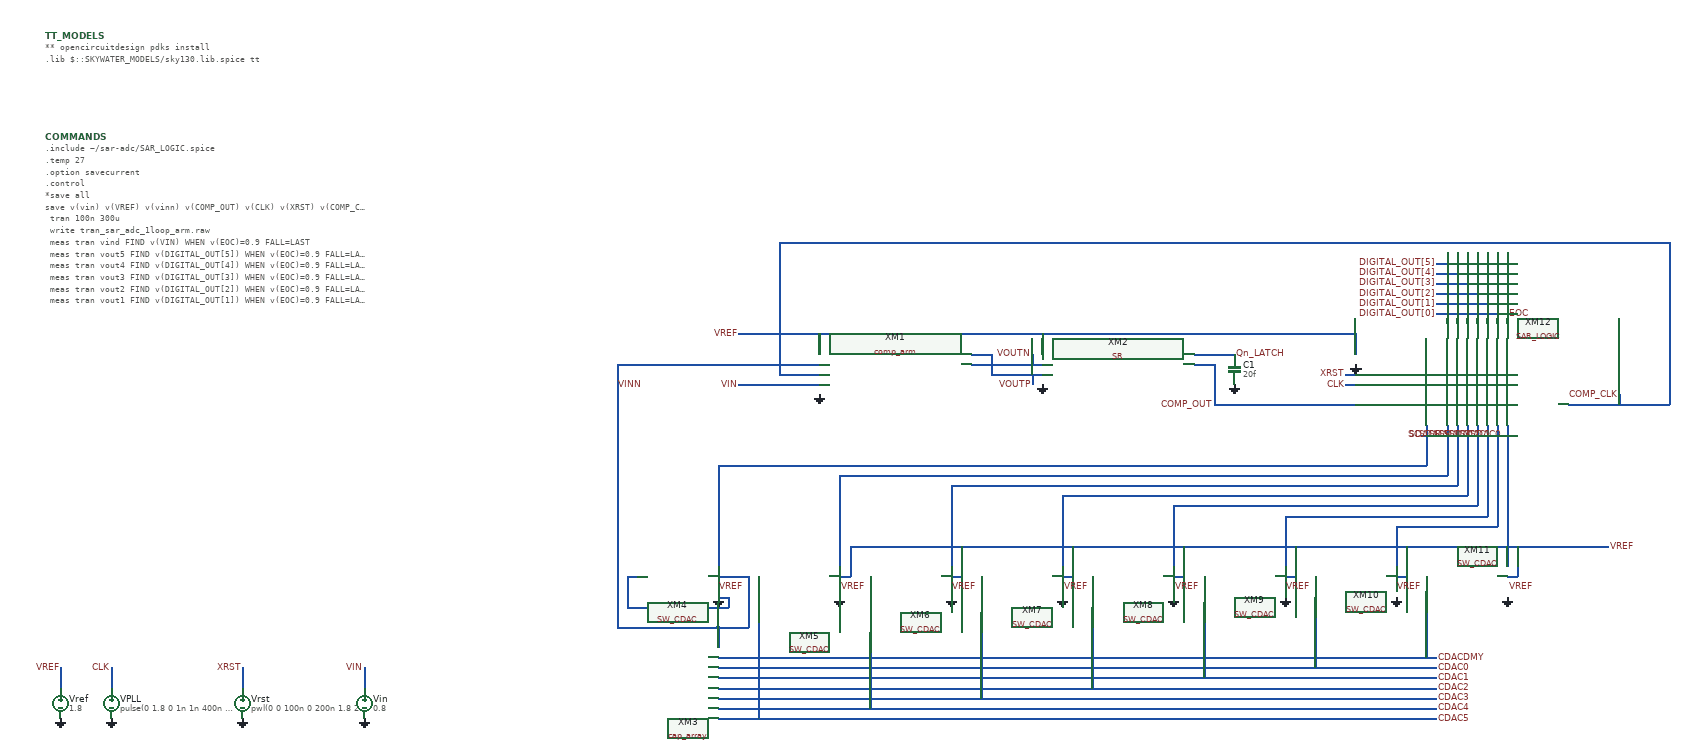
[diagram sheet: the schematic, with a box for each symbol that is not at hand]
v {xschem version=3.4.8RC file_version=1.3}
G {}
K {}
V {}
S {}
F {}
E {}
N 60 -300 60 -260 {
lab=VREF}
N 160 -300 160 -260 {
lab=CLK}
N 420 -300 420 -260 {
lab=XRST}
N 660 -300 660 -260 {
lab=VIN}
N 2340 -820 2620 -820 {
lab=COMP_OUT}
N 2600 -860 2620 -860 {
lab=CLK}
N 2600 -880 2620 -880 {
lab=XRST}
N 2920 -780 2920 -690 {
lab=SDAC0}
N 2910 -760 2920 -760 {
lab=SDAC0}
N 2900 -780 2900 -690 {
lab=SDAC1}
N 2890 -760 2900 -760 {
lab=SDAC1}
N 2880 -780 2880 -690 {
lab=SDAC2}
N 2870 -760 2880 -760 {
lab=SDAC2}
N 2860 -780 2860 -690 {
lab=SDAC3}
N 2850 -760 2860 -760 {
lab=SDAC3}
N 2840 -780 2840 -690 {
lab=SDAC4}
N 2830 -760 2840 -760 {
lab=SDAC4}
N 2820 -780 2820 -690 {
lab=SDAC5}
N 2810 -760 2820 -760 {
lab=SDAC5}
N 2800 -780 2800 -690 {
lab=SDAC6}
N 2790 -760 2800 -760 {
lab=SDAC6}
N 2760 -780 2760 -700 {
lab=SC}
N 2750 -760 2760 -760 {
lab=SC}
N 3040 -820 3240 -820 {
lab=COMP_CLK}
N 3140 -840 3140 -820 {
lab=COMP_CLK}
N 1860 -920 1900 -920 {
lab=VOUTP}
N 1860 -900 1880 -900 {
lab=VOUTN}
N 1360 -320 2780 -320 {
lab=CDACDMY}
N 1360 -300 2780 -300 {
lab=CDAC0}
N 1360 -280 2780 -280 {
lab=CDAC1}
N 1360 -260 2780 -260 {
lab=CDAC2}
N 1360 -240 2780 -240 {
lab=CDAC3}
N 1360 -220 2780 -220 {
lab=CDAC4}
N 1360 -200 2780 -200 {
lab=CDAC5}
N 1600 -680 2800 -680 {
lab=SDAC6}
N 1600 -680 1600 -500 {
lab=SDAC6}
N 1820 -660 1820 -500 {
lab=SDAC5}
N 1820 -660 2820 -660 {
lab=SDAC5}
N 2040 -640 2840 -640 {
lab=SDAC4}
N 2040 -640 2040 -500 {
lab=SDAC4}
N 2260 -620 2260 -500 {
lab=SDAC3}
N 2260 -620 2860 -620 {
lab=SDAC3}
N 2480 -600 2880 -600 {
lab=SDAC2}
N 2480 -600 2480 -500 {
lab=SDAC2}
N 2700 -580 2700 -500 {
lab=SDAC1}
N 2920 -690 2920 -500 {
lab=SDAC0}
N 1360 -700 2760 -700 {
lab=SC}
N 1360 -700 1360 -500 {
lab=SC}
N 1180 -480 1200 -480 {
lab=GND}
N 1180 -480 1180 -420 {
lab=GND}
N 1180 -420 1380 -420 {
lab=GND}
N 1380 -440 1380 -420 {
lab=GND}
N 1360 -440 1380 -440 {
lab=GND}
N 1360 -380 1360 -340 {
lab=VINN}
N 1160 -380 1360 -380 {
lab=VINN}
N 1160 -900 1160 -380 {
lab=VINN}
N 1160 -900 1560 -900 {
lab=VINN}
N 1360 -480 1420 -480 {
lab=VINN}
N 1420 -480 1420 -380 {
lab=VINN}
N 1360 -380 1420 -380 {
lab=VINN}
N 2700 -580 2900 -580 {
lab=SDAC1}
N 1480 -880 1560 -880 {
lab=COMP_CLK}
N 1480 -1140 1480 -880 {
lab=COMP_CLK}
N 1480 -1140 3240 -1140 {
lab=COMP_CLK}
N 3240 -1140 3240 -820 {
lab=COMP_CLK}
N 1620 -540 3120 -540 {
lab=VREF}
N 1600 -480 1620 -480 {
lab=VREF}
N 1620 -540 1620 -480 {
lab=VREF}
N 1820 -480 1840 -480 {
lab=VREF}
N 1840 -540 1840 -480 {
lab=VREF}
N 2040 -480 2060 -480 {
lab=VREF}
N 2060 -540 2060 -480 {
lab=VREF}
N 2260 -480 2280 -480 {
lab=VREF}
N 2280 -540 2280 -480 {
lab=VREF}
N 2480 -480 2500 -480 {
lab=VREF}
N 2500 -540 2500 -480 {
lab=VREF}
N 2700 -480 2720 -480 {
lab=VREF}
N 2720 -540 2720 -480 {
lab=VREF}
N 2920 -480 2940 -480 {
lab=VREF}
N 2940 -540 2940 -480 {
lab=VREF}
N 1400 -860 1560 -860 {
lab=VIN}
N 1980 -880 1980 -860 {
lab=VOUTP}
N 1980 -920 1980 -900 {
lab=VOUTN}
N 2800 -690 2800 -680 {
lab=SDAC6}
N 2820 -690 2820 -660 {
lab=SDAC5}
N 2840 -690 2840 -640 {
lab=SDAC4}
N 2860 -690 2860 -620 {
lab=SDAC3}
N 2880 -690 2880 -600 {
lab=SDAC2}
N 2900 -690 2900 -580 {
lab=SDAC1}
N 1880 -480 1880 -240 {
lab=CDAC3}
N 1660 -480 1660 -220 {
lab=CDAC4}
N 1440 -480 1440 -200 {
lab=CDAC5}
N 2800 -1120 2800 -980 {
lab=DIGITAL_OUT[5]}
N 2780 -1100 2800 -1100 {
lab=DIGITAL_OUT[5]}
N 2780 -1080 2820 -1080 {
lab=DIGITAL_OUT[4]}
N 2780 -1060 2840 -1060 {
lab=DIGITAL_OUT[3]}
N 2780 -1040 2860 -1040 {
lab=DIGITAL_OUT[2]}
N 2780 -1020 2880 -1020 {
lab=DIGITAL_OUT[1]}
N 2780 -1000 2900 -1000 {
lab=DIGITAL_OUT[0]}
N 2820 -1120 2820 -980 {
lab=DIGITAL_OUT[4]}
N 2840 -1120 2840 -980 {
lab=DIGITAL_OUT[3]}
N 2860 -1120 2860 -980 {
lab=DIGITAL_OUT[2]}
N 2880 -1120 2880 -980 {
lab=DIGITAL_OUT[1]}
N 2900 -1120 2900 -980 {
lab=DIGITAL_OUT[0]}
N 2920 -1120 2920 -980 {
lab=EOC}
N 2100 -480 2100 -260 {lab=CDAC2}
N 2320 -480 2320 -280 {lab=CDAC1}
N 2540 -480 2540 -300 {lab=CDAC0}
N 2760 -480 2760 -320 {lab=CDACDMY}
N 1400 -960 2620 -960 {lab=VREF}
N 2620 -960 2620 -920 {lab=VREF}
N 2000 -960 2000 -920 {lab=VREF}
N 1560 -960 1560 -920 {lab=VREF}
N 2360 -920 2380 -920 {lab=Qn_LATCH}
N 2300 -900 2340 -900 {lab=COMP_OUT}
N 2340 -900 2340 -820 {lab=COMP_OUT}
N 2300 -920 2360 -920 {lab=Qn_LATCH}
N 1880 -900 2000 -900 {lab=VOUTN}
N 1900 -920 1900 -880 {lab=VOUTP}
N 1900 -880 2000 -880 {lab=VOUTP}
C {devices/vsource.sym} 60 -230 0 0 {name=Vref value=1.8 savecurrent=false}
C {devices/gnd.sym} 160 -200 0 0 {name=l2 lab=GND}
C {devices/gnd.sym} 60 -200 0 0 {name=l3 lab=GND}
C {devices/lab_pin.sym} 160 -300 0 0 {name=p2 sig_type=std_logic lab=CLK}
C {devices/lab_pin.sym} 420 -300 0 0 {name=p9 sig_type=std_logic lab=XRST}
C {devices/gnd.sym} 420 -200 0 0 {name=l1 lab=GND}
C {devices/lab_pin.sym} 660 -300 2 1 {name=p25 sig_type=std_logic lab=VIN}
C {devices/gnd.sym} 660 -200 0 0 {name=l22 lab=GND}
C {devices/code.sym} 30 -1550 0 0 {name=TT_MODELS
only_toplevel=true
format="tcleval( @value )"
value="
** opencircuitdesign pdks install
.lib $::SKYWATER_MODELS/sky130.lib.spice tt
"
spice_ignore=false}
C {devices/vsource.sym} 160 -230 0 0 {name=VPLL value="pulse(0 1.8 0 1n 1n 400n 800n)" savecurrent=false}
C {devices/vsource.sym} 420 -230 0 0 {name=Vrst value="pwl(0 0 100n 0 200n 1.8 200n 1.8)" savecurrent=false}
C {devices/vsource.sym} 660 -230 0 0 {name=Vin value=0.8 savecurrent=false}
C {devices/lab_pin.sym} 60 -300 2 1 {name=p45 sig_type=std_logic lab=VREF}
C {devices/simulator_commands_shown.sym} 30 -1350 0 0 {name=COMMANDS
simulator=ngspice
only_toplevel=false 
value=".include ~/sar-adc/SAR_LOGIC.spice
.temp 27
.option savecurrent
.control
*save all
save v(vin) v(VREF) v(vinn) v(COMP_OUT) v(CLK) v(XRST) v(COMP_CLK) v(eoc) v(CDACDMY) v(CDAC0) v(CDAC1) v(CDAC2) v(CDAC3) v(CDAC4) v(CDAC5) v(digital_out[5]) v(digital_out[4]) v(digital_out[3]) v(digital_out[2]) v(digital_out[1]) v(digital_out[0]) v(SC) v(SDAC0) v(SDAC1) v(SDAC2) v(SDAC3) v(SDAC4) v(SDAC5) v(SDAC6)



	tran 100n 300u
	write tran_sar_adc_1loop_arm.raw
	meas tran vind FIND v(VIN) WHEN v(EOC)=0.9 FALL=LAST
	meas tran vout5 FIND v(DIGITAL_OUT[5]) WHEN v(EOC)=0.9 FALL=LAST
	meas tran vout4 FIND v(DIGITAL_OUT[4]) WHEN v(EOC)=0.9 FALL=LAST
	meas tran vout3 FIND v(DIGITAL_OUT[3]) WHEN v(EOC)=0.9 FALL=LAST
	meas tran vout2 FIND v(DIGITAL_OUT[2]) WHEN v(EOC)=0.9 FALL=LAST
	meas tran vout1 FIND v(DIGITAL_OUT[1]) WHEN v(EOC)=0.9 FALL=LAST
	meas tran vout0 FIND v(DIGITAL_OUT[0]) WHEN v(EOC)=0.9 FALL=LAST
	print vind >> tran_sar_adc_1loop_out_typ.txt
*	print vinn >> tran_sar_adc_1loop_out_typ.txt
	print vout5 >> tran_sar_adc_1loop_out_typ.txt
	print vout4 >> tran_sar_adc_1loop_out_typ.txt
	print vout3 >> tran_sar_adc_1loop_out_typ.txt
	print vout2 >> tran_sar_adc_1loop_out_typ.txt
	print vout1 >> tran_sar_adc_1loop_out_typ.txt
	print vout0 >> tran_sar_adc_1loop_out_typ.txt

.endc
"}
C {devices/lab_pin.sym} 2600 -860 0 0 {name=p5 sig_type=std_logic lab=CLK}
C {devices/lab_pin.sym} 2600 -880 0 0 {name=p7 sig_type=std_logic lab=XRST}
C {devices/lab_pin.sym} 2910 -760 3 0 {name=p10 sig_type=std_logic lab=SDAC0}
C {devices/lab_pin.sym} 2890 -760 3 0 {name=p11 sig_type=std_logic lab=SDAC1}
C {devices/lab_pin.sym} 2870 -760 3 0 {name=p12 sig_type=std_logic lab=SDAC2}
C {devices/lab_pin.sym} 2850 -760 3 0 {name=p13 sig_type=std_logic lab=SDAC3}
C {devices/lab_pin.sym} 2830 -760 3 0 {name=p14 sig_type=std_logic lab=SDAC4}
C {devices/lab_pin.sym} 2810 -760 3 0 {name=p15 sig_type=std_logic lab=SDAC5}
C {devices/lab_pin.sym} 2790 -760 3 0 {name=p16 sig_type=std_logic lab=SDAC6}
C {devices/lab_pin.sym} 2750 -760 3 0 {name=p19 sig_type=std_logic lab=SC}
C {devices/lab_pin.sym} 3140 -840 0 0 {name=p20 sig_type=std_logic lab=COMP_CLK}
C {devices/gnd.sym} 1360 -440 0 1 {name=l4 lab=GND}
C {devices/gnd.sym} 1600 -440 0 1 {name=l5 lab=GND}
C {devices/gnd.sym} 1820 -440 0 1 {name=l6 lab=GND}
C {devices/gnd.sym} 2040 -440 0 1 {name=l7 lab=GND}
C {devices/gnd.sym} 2260 -440 0 1 {name=l8 lab=GND}
C {devices/gnd.sym} 2480 -440 0 1 {name=l9 lab=GND}
C {devices/gnd.sym} 2700 -440 0 1 {name=l10 lab=GND}
C {devices/gnd.sym} 2920 -440 0 1 {name=l11 lab=GND}
C {devices/gnd.sym} 2620 -900 0 1 {name=l16 lab=GND}
C {devices/gnd.sym} 1560 -840 0 1 {name=l18 lab=GND}
C {devices/gnd.sym} 2000 -860 0 1 {name=l19 lab=GND}
C {devices/gnd.sym} 2380 -860 0 1 {name=l20 lab=GND}
C {devices/lab_pin.sym} 1400 -860 0 0 {name=p26 sig_type=std_logic lab=VIN}
C {devices/lab_pin.sym} 1980 -920 0 0 {name=p27 sig_type=std_logic lab=VOUTN}
C {devices/lab_pin.sym} 1980 -860 2 1 {name=p28 sig_type=std_logic lab=VOUTP}
C {devices/lab_pin.sym} 2780 -260 0 1 {name=p29 sig_type=std_logic lab=CDAC2}
C {devices/lab_pin.sym} 2780 -280 0 1 {name=p30 sig_type=std_logic lab=CDAC1}
C {devices/lab_pin.sym} 2780 -300 0 1 {name=p31 sig_type=std_logic lab=CDAC0}
C {devices/lab_pin.sym} 2780 -320 0 1 {name=p32 sig_type=std_logic lab=CDACDMY}
C {devices/lab_pin.sym} 2780 -240 0 1 {name=p33 sig_type=std_logic lab=CDAC3}
C {devices/lab_pin.sym} 2780 -220 0 1 {name=p34 sig_type=std_logic lab=CDAC4}
C {devices/lab_pin.sym} 2780 -200 0 1 {name=p35 sig_type=std_logic lab=CDAC5}
C {devices/lab_pin.sym} 1160 -860 0 1 {name=p36 sig_type=std_logic lab=VINN}
C {devices/lab_pin.sym} 3120 -540 2 0 {name=p37 sig_type=std_logic lab=VREF}
C {devices/lab_pin.sym} 2380 -920 2 0 {name=p38 sig_type=std_logic lab=Qn_LATCH}
C {devices/lab_pin.sym} 2340 -820 0 0 {name=p39 sig_type=std_logic lab=COMP_OUT}
C {devices/lab_pin.sym} 2780 -1100 0 0 {name=p18 sig_type=std_logic lab=DIGITAL_OUT[5]}
C {devices/lab_pin.sym} 2780 -1080 0 0 {name=p21 sig_type=std_logic lab=DIGITAL_OUT[4]}
C {devices/lab_pin.sym} 2780 -1060 0 0 {name=p40 sig_type=std_logic lab=DIGITAL_OUT[3]}
C {devices/lab_pin.sym} 2780 -1040 0 0 {name=p41 sig_type=std_logic lab=DIGITAL_OUT[2]}
C {devices/lab_pin.sym} 2780 -1020 0 0 {name=p42 sig_type=std_logic lab=DIGITAL_OUT[1]}
C {devices/lab_pin.sym} 2780 -1000 0 0 {name=p43 sig_type=std_logic lab=DIGITAL_OUT[0]}
C {devices/lab_pin.sym} 2920 -1000 2 0 {name=p17 sig_type=std_logic lab=EOC}
C {SR.sym} 2150 -890 0 0 {name=XM2
spiceprefix=X
}
C {SAR_LOGIC.sym} 2830 -870 0 0 {name=XM12 prefix=SAR_LOGIC}
C {cap_array.sym} 1210 -270 0 0 {name=XM3
spiceprefix=X}
C {SW_CDAC.sym} 1360 -500 0 1 {name=XM4
spiceprefix=X}
C {SW_CDAC.sym} 1600 -500 0 1 {name=XM5
spiceprefix=X}
C {SW_CDAC.sym} 1820 -500 0 1 {name=XM6
spiceprefix=X}
C {SW_CDAC.sym} 2040 -500 0 1 {name=XM7
spiceprefix=X}
C {SW_CDAC.sym} 2260 -500 0 1 {name=XM8
spiceprefix=X}
C {SW_CDAC.sym} 2480 -500 0 1 {name=XM9
spiceprefix=X}
C {SW_CDAC.sym} 2700 -500 0 1 {name=XM10
spiceprefix=X}
C {SW_CDAC.sym} 2920 -500 0 1 {name=XM11
spiceprefix=X}
C {devices/lab_pin.sym} 1400 -960 2 1 {name=p1 sig_type=std_logic lab=VREF}
C {devices/lab_pin.sym} 2920 -460 2 0 {name=p3 sig_type=std_logic lab=VREF}
C {devices/lab_pin.sym} 2700 -460 2 0 {name=p4 sig_type=std_logic lab=VREF}
C {devices/lab_pin.sym} 2480 -460 2 0 {name=p6 sig_type=std_logic lab=VREF}
C {devices/lab_pin.sym} 2260 -460 2 0 {name=p8 sig_type=std_logic lab=VREF}
C {devices/lab_pin.sym} 2040 -460 2 0 {name=p22 sig_type=std_logic lab=VREF}
C {devices/lab_pin.sym} 1820 -460 2 0 {name=p23 sig_type=std_logic lab=VREF}
C {devices/lab_pin.sym} 1600 -460 2 0 {name=p24 sig_type=std_logic lab=VREF}
C {devices/lab_pin.sym} 1360 -460 2 0 {name=p44 sig_type=std_logic lab=VREF}
C {comp_arm.sym} 1710 -880 0 0 {name=XM1
spiceprefix=X}
C {devices/capa.sym} 2380 -890 0 0 {name=C1
m=1
value=20f
footprint=1206
device="ceramic capacitor"}
